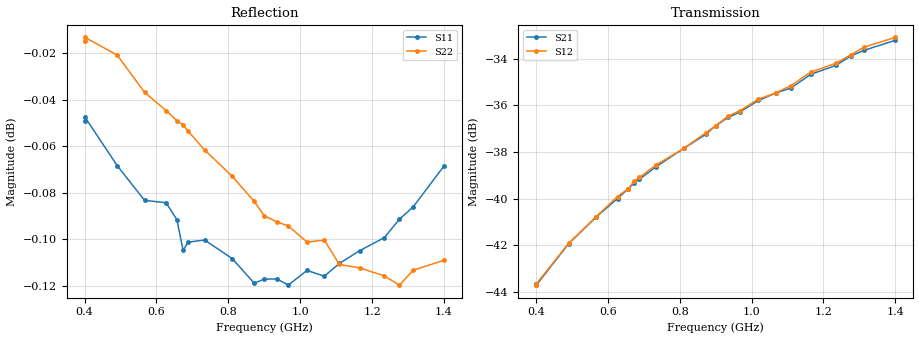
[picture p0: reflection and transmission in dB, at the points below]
#  HZ  S  RI  R  50.00
! Rohde & Schwarz Vector Network Analyzer
! Rohde-Schwarz,ZNLE3-2Port,1323001253100757,1.02.1.9
! Created: UTC 12/6/2017, 4:37:07 PM
! freq[Hz]  re:S11  im:S11  re:S21  im:S21  re:S12  im:S12  re:S22  im:S22
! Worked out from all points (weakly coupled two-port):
!   1001 points, 400 MHz to 1.4 GHz, reference 50 ohm
!   highest |S21| = -33.22 dB at 1.4 GHz (marker M1); lowest = -43.7 dB at 401 MHz (marker M2)
!   lowest |S11| = -0.1 dB at 967 MHz (marker M3), VSWR 145.41, Z = 6.33e+03 - j2.44e+03 ohm
!   |S11| at or under -10 dB: nowhere
!   |S22| runs from -0.1 to 0.0 dB; largest |S21 - S12| = 0.00044
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4e8  0.9943 0.00962  -0.000271 0.00654  -0.000306 0.00653  0.9982 0.0133
4.01e8  0.9945 0.00979  -0.000252 0.00652  -0.000243 0.00656  0.9984 0.0132
4.91e8  0.9921 0.0104  -0.000289 0.008  -0.000265 0.00802  0.9975 0.0146
5.67e8  0.9904 0.0105  -0.000283 0.00912  -0.000252 0.00914  0.9957 0.0117
6.27e8  0.9903 0.00899  -0.000397 0.01  -0.00039 0.0101  0.9948 0.012
6.57e8  0.9894 0.0141  -0.000409 0.0105  -0.000535 0.0105  0.9943 0.0119
6.74e8  0.988 0.00377  -0.000459 0.0108  -0.000558 0.0109  0.9941 0.0121
6.88e8  0.9884 0.0038  -0.00048 0.011  -0.000484 0.0111  0.9938 0.0109
7.34e8  0.9885 0.00533  -0.000423 0.0117  -0.000483 0.0118  0.9929 0.00793
8.11e8  0.9876 0.00122  -0.000654 0.0128  -0.000697 0.0128  0.9916 0.00836
8.72e8  0.9864 -0.000259  -0.000963 0.0137  -0.000956 0.0138  0.9904 0.00261
9e8  0.9866 -0.00189  -0.00107 0.0143  -0.00116 0.0143  0.9897 0.0015
9.35e8  0.9866 -0.00359  -0.0011 0.0149  -0.00111 0.015  0.9894 0.00153
9.67e8  0.9863 -0.00524  -0.00108 0.0153  -0.00107 0.0154  0.9892 -0.000387
1.019e9  0.987 -0.00669  -0.0012 0.0162  -0.00134 0.0163  0.9884 -0.00481
1.067e9  0.9867 -0.00926  -0.0013 0.0168  -0.00134 0.0168  0.9885 -0.0048
1.109e9  0.9873 -0.0115  -0.00158 0.0172  -0.00169 0.0174  0.9873 -0.00549
1.165e9  0.9879 -0.0131  -0.00182 0.0184  -0.00185 0.0186  0.9871 -0.00986
1.234e9  0.9885 -0.0161  -0.00205 0.0192  -0.00216 0.0194  0.9867 -0.0107
1.276e9  0.9894 -0.0162  -0.00238 0.0201  -0.00248 0.0202  0.9862 -0.0145
1.314e9  0.99 -0.0162  -0.00229 0.0207  -0.00253 0.021  0.9869 -0.0162
1.4e9  0.992 -0.017  -0.00269 0.0217  -0.00286 0.022  0.9874 -0.0156
